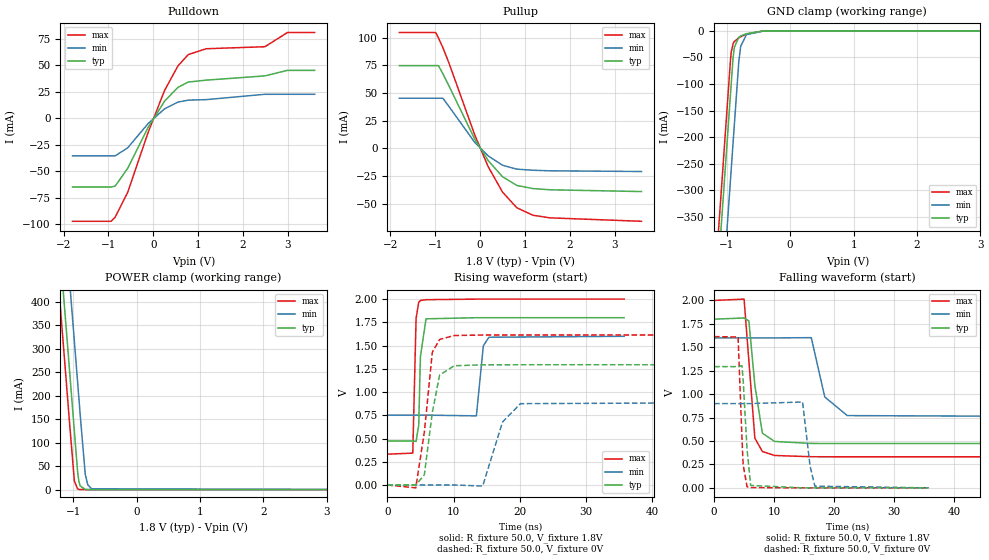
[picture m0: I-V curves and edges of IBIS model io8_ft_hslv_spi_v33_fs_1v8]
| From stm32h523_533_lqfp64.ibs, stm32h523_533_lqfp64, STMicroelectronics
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[Model]   io8_ft_hslv_spi_v33_fs_1v8
Model_type I/O
Polarity   Non-Inverting
Enable   Active-Low
| CAP_THRESHOLD on pad IOFT is "UDTCAPC" :
| Rising=20.0% of vddiom   Falling=80.0% of vddiom
| C_comp min and max val. don't necessarily correlate with the min and max pvt
| but are the smallest and greatest pad capacitance found.
| var   typ   min   max
C_comp   3.69213pF  3.66975pF  3.86731pF
|C_comp_pullup   2.29905pF  2.22610pF  2.22535pF
|C_comp_pulldown   1.39308pF  1.44365pF  1.64196pF
Vinl = 480.0mV
Vinh = 1.4V
Vmeas = 900.0mV   | Reference voltage for timing measurements
Cref  = 50.0pF   | Timing specification test load capacitance value
Rref  = 100.0MOhm   | Timing specification test load resistance value
Vref  = 900.0mV   | Timing specification test load voltage
[Model Spec]
| TIME_THRESHOLD on pin ZIV33M is "CMOS" :
| Rising=40.0% of vddiom   Falling=60.0% of vddiom
Vinl 693.80000mV 621.80000mV 774.80000mV
Vinh 1.05820V 933.20000mV 1.16320V
| variable   typ   min   max
[Temperature Range] 25.0 125.0 -40.0
| variable   typ   min   max
[Voltage Range] 1.8V 1.6V 2.0V
| variable   typ   min   max
[POWER Clamp Reference] 1.8V 1.6V 2.0V
| variable   typ   min   max
[GND Clamp Reference] 0V 0V 0V
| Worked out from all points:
|   slope of the pulldown table from 0 to 0.27 V, typ, clamps not added: 15.8 ohm
|   slope of the pullup table from 0 to 0.27 V, typ, clamps not added: 17.1 ohm
|   GND clamp passes 1 mA (typ) near -0.52 V on its own axis
|   POWER clamp passes 1 mA (typ) near -0.84 V on its own axis
|   rising waveform, R_fixture 50.0, V_fixture 1.8V: 20-80 % time 285ps typ, 440ps min, 245ps max; typ from 0.474 V to 1.8 V
|   falling waveform, R_fixture 50.0, V_fixture 1.8V: 20-80 % time 1.13ns typ, 2.11ns min, 1.05ns max; typ from 1.8 V to 0.474 V
|   rising waveform, R_fixture 50.0, V_fixture 0V: 20-80 % time 1.38ns typ, 2.22ns min, 1.22ns max; typ from 0 V to 1.29 V
|   falling waveform, R_fixture 50.0, V_fixture 0V: 20-80 % time 734ps typ, 1.02ns min, 551ps max; typ from 1.29 V to 0 V
[POWER Clamp]
-1.8V     1.518A     1.709A     1.407A
-1.23V    548.8mA    740.2mA    437.5mA
-1.16V    429.8mA    621.2mA    318.5mA
-1.05V    242.8mA    434.2mA    131.5mA
-980mV    123.8mA    315.2mA    17.95mA
-930mV    38.81mA    230.2mA    1.49mA
-910mV    17.82mA    196.2mA    550.8uA
-890mV    8.18mA     162.2mA    203.5uA
-810mV    363.5uA    33.6mA     3.797uA
-770mV    76.62uA    10.47mA    518.8nA
-710mV    7.416uA    1.822mA    26.33nA
3.6V      0A         0A         0A
[GND Clamp]
-1.8V     -1.579A    -1.74A     -1.515A
-1.24V    -627.3mA   -788.3mA   -562.7mA
-1.05V    -304.3mA   -465.3mA   -239.7mA
-940mV    -117.3mA   -278.3mA   -52.69mA
-930mV    -100.3mA   -261.3mA   -40.52mA
-900mV    -50.11mA   -210.3mA   -24.23mA
-880mV    -30.95mA   -176.3mA   -20.02mA
-810mV    -12.18mA   -57.97mA   -13.23mA
-780mV    -9.807mA   -29.1mA    -11.19mA
-690mV    -5.41mA    -7.142mA   -6.184mA
-420mV    -170.4uA   -446.1uA   -81.94uA
3.6V      5.755nA    953.2nA    228.2pA
| variable   typ   min   max
[Pullup Reference] 1.8V 1.6V 2.0V
| variable   typ   min   max
[Pulldown Reference] 0V 0V 0V
[Pullup]
-1.8V     74.76mA    45.28mA    104.6mA
-990mV    74.76mA    45.28mA    104.6mA
-930mV    74.76mA    45.28mA    99.84mA
-830mV    67.43mA    45.28mA    91.04mA
-680mV    55.26mA    37.06mA    75.52mA
-120mV    8.372mA    5.391mA    12.2mA
180mV     -11.02mA   -6.852mA   -16.51mA
500mV     -25.64mA   -15.26mA   -39.49mA
820mV     -33.51mA   -18.79mA   -53.71mA
1.18V     -36.34mA   -19.79mA   -60.45mA
1.56V     -37.44mA   -20.28mA   -62.79mA
3.6V      -39.03mA   -20.93mA   -65.9mA
[Pulldown]
-1.8V     -65.02mA   -35.56mA   -97.42mA
-940mV    -65.02mA   -35.56mA   -97.42mA
-850mV    -64.17mA   -35.56mA   -93.49mA
-570mV    -47.32mA   -28.01mA   -70.04mA
-120mV    -9.088mA   -5.279mA   -14.07mA
250mV     16.04mA    8.832mA    26.05mA
550mV     29.17mA    15.25mA    49.41mA
780mV     34.17mA    17.07mA    60.14mA
1.18V     35.97mA    17.56mA    65.65mA
2.49V     40mA       22.62mA    67.56mA
2.99V     45.21mA    22.62mA    80.94mA
3.6V      45.21mA    22.62mA    80.94mA
[Ramp]
dV/dt_r 776.15948mV/1.37726ns 539.55921mV/2.1654ns 968.54348mV/1.22042ns
dV/dt_f 795.78715mV/1.12648ns 508.98185mV/1.87644ns 1.00099V/1.03717ns
R_load = 50.0
| Removed startup time: 0s 0s 0s  .
| Removed end time: 35.75ns.
[Rising Waveform]
R_fixture   = 50.0
V_fixture   = 1.8V
V_fixture_min = 1.6V
V_fixture_max = 2.0V
0s        473.7mV    751.7mV    331.7mV
3.85ns    473.7mV    751.7mV    342.8mV
4.35ns    468.7mV    751.7mV    1.792V
4.75ns    642.9mV    751.7mV    1.966V
5ns       1.379V     751.7mV    1.985V
5.85ns    1.788V     751.7mV    1.994V
13.45ns   1.8V       743.8mV    2V
14.5ns    1.8V       1.498V     2V
15.35ns   1.8V       1.59V      2V
35.75ns   1.8V       1.6V       2V
| Removed startup time: 0s 0s 0s  .
| Removed end time: 98.75ns.
[Falling Waveform]
R_fixture   = 50.0
V_fixture   = 1.8V
V_fixture_min = 1.6V
V_fixture_max = 2.0V
0s        1.8V       1.6V       2V
5ns       1.813V     1.6V       2.014V
5.8ns     1.781V     1.6V       1.356V
6.8ns     1.095V     1.6V       529.5mV
8.05ns    583.6mV    1.6V       387.9mV
10.1ns    495.2mV    1.6V       345.5mV
16.2ns    474.1mV    1.603V     332.1mV
18.45ns   473.8mV    969.8mV    331.8mV
22.2ns    473.7mV    771.1mV    331.7mV
98.75ns   473.7mV    751.7mV    331.7mV
| Removed startup time: 0s 0s 0s  .
| Removed end time: 98.6ns.
[Rising Waveform]
R_fixture   = 50.0
V_fixture   = 0V
V_fixture_min = 0V
V_fixture_max = 0V
0s        174.5nV    438.2nV    123.6nV
4.3ns     -1.03mV    437.8nV    -30.91mV
5.6ns     110.8mV    409.4nV    570.7mV
6.8ns     781.2mV    356nV      1.428V
7.9ns     1.183V     290.5nV    1.566V
10.1ns    1.283V     278.9nV    1.608V
14.4ns    1.293V     -11.09mV   1.614V
17.4ns    1.293V     678.1mV    1.614V
20.1ns    1.294V     875.2mV    1.614V
98.6ns    1.294V     899.3mV    1.614V
| Removed startup time: 0s 0s 0s  .
| Removed end time: 35.75ns.
[Falling Waveform]
R_fixture   = 50.0
V_fixture   = 0V
V_fixture_min = 0V
V_fixture_max = 0V
0s        1.294V     899.3mV    1.614V
4ns       1.294V     899.3mV    1.61V
4.65ns    1.303V     899.3mV    532.7mV
4.85ns    1.148V     899.3mV    245.4mV
5.5ns     406.5mV    899.3mV    10.5mV
6.1ns     26.09mV    899.3mV    3.023mV
14.75ns   42.68uV    916.2mV    30.09uV
16ns      26.47uV    232.4mV    16.51uV
16.8ns    20.02uV    18.32mV    11.33uV
35.75ns   156.7nV    11.83uV    32.96nV
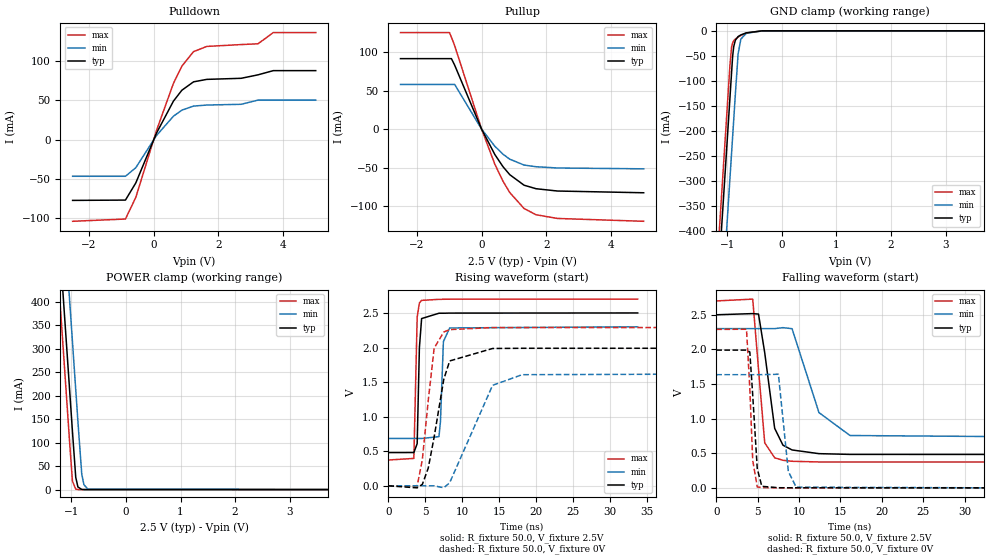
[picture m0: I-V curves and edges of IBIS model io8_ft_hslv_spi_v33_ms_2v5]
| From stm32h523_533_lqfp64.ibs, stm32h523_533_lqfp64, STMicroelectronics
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[Model]   io8_ft_hslv_spi_v33_ms_2v5
Model_type I/O
Polarity   Non-Inverting
Enable   Active-Low
| CAP_THRESHOLD on pad IOFT is "UDTCAPC" :
| Rising=20.0% of vddiom   Falling=80.0% of vddiom
| C_comp min and max val. don't necessarily correlate with the min and max pvt
| but are the smallest and greatest pad capacitance found.
| var   typ   min   max
C_comp   3.86841pF  3.83555pF  3.96274pF
|C_comp_pullup   2.45390pF  2.33575pF  2.34220pF
|C_comp_pulldown   1.41451pF  1.49980pF  1.62054pF
Vinl = 690.0mV
Vinh = 1.89V
Vmeas = 1.25V   | Reference voltage for timing measurements
Cref  = 50.0pF   | Timing specification test load capacitance value
Rref  = 100.0MOhm   | Timing specification test load resistance value
Vref  = 1.25V   | Timing specification test load voltage
[Model Spec]
| TIME_THRESHOLD on pin ZIV33M is "CMOS" :
| Rising=40.0% of vddiom   Falling=60.0% of vddiom
Vinl 978.80000mV 906.80000mV 1.05480V
Vinh 1.39920V 1.29220V 1.48720V
| variable   typ   min   max
[Temperature Range] 25.0 125.0 -40.0
| variable   typ   min   max
[Voltage Range] 2.5V 2.3V 2.7V
| variable   typ   min   max
[POWER Clamp Reference] 2.5V 2.3V 2.7V
| variable   typ   min   max
[GND Clamp Reference] 0V 0V 0V
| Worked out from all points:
|   slope of the pulldown table from 0 to 0.375 V, typ, clamps not added: 11.5 ohm
|   slope of the pullup table from 0 to 0.375 V, typ, clamps not added: 12.3 ohm
|   GND clamp passes 1 mA (typ) near -0.52 V on its own axis
|   POWER clamp passes 1 mA (typ) near -0.84 V on its own axis
|   rising waveform, R_fixture 50.0, V_fixture 2.5V: 20-80 % time 253ps typ, 302ps min, 243ps max; typ from 0.481 V to 2.5 V
|   falling waveform, R_fixture 50.0, V_fixture 2.5V: 20-80 % time 1.32ns typ, 2.74ns min, 855ps max; typ from 2.5 V to 0.481 V
|   rising waveform, R_fixture 50.0, V_fixture 0V: 20-80 % time 1.91ns typ, 3.42ns min, 1.29ns max; typ from 0 V to 1.99 V
|   falling waveform, R_fixture 50.0, V_fixture 0V: 20-80 % time 576ps typ, 771ps min, 459ps max; typ from 1.99 V to 0 V
[POWER Clamp]
-2.5V     2.708A     2.899A     2.597A
-1.23V    548.8mA    740.2mA    437.5mA
-1.16V    429.8mA    621.2mA    318.5mA
-1.12V    361.8mA    553.2mA    250.5mA
-1.03V    208.8mA    400.2mA    97.53mA
-980mV    123.8mA    315.2mA    17.95mA
-920mV    26.3mA     213.2mA    906uA
-880mV    5.543mA    145.2mA    123.7uA
-810mV    363.5uA    33.6mA     3.797uA
-770mV    76.62uA    10.47mA    518.8nA
-700mV    5.026uA    1.361mA    16.09nA
5V        0A         0A         0A
[GND Clamp]
-2.5V     -2.77A     -2.931A    -2.704A
-1.21V    -576.8mA   -738.1mA   -511.3mA
-950mV    -134.8mA   -296.1mA   -69.34mA
-920mV    -83.82mA   -245.1mA   -32.48mA
-900mV    -50.56mA   -211.1mA   -24.02mA
-880mV    -31.31mA   -177.1mA   -19.85mA
-850mV    -18.7mA    -126.1mA   -16.34mA
-800mV    -11.46mA   -46.18mA   -12.45mA
-750mV    -8.203mA   -16.63mA   -9.325mA
-650mV    -4.063mA   -4.987mA   -4.427mA
-360mV    -35.05uA   -165.1uA   -9.564uA
5V        7.96nA     1.282uA    294pA
| variable   typ   min   max
[Pullup Reference] 2.5V 2.3V 2.7V
| variable   typ   min   max
[Pulldown Reference] 0V 0V 0V
[Pullup]
-2.5V     91.39mA    57.92mA    125.2mA
-990mV    91.39mA    57.92mA    125.2mA
-930mV    91.39mA    57.92mA    119.1mA
-830mV    82.91mA    57.92mA    108.2mA
0V        9.32pA     735pA      5.94pA
410mV     -33.05mA   -22.3mA    -45.65mA
660mV     -48.74mA   -32.53mA   -67.55mA
870mV     -59.15mA   -39.06mA   -82.32mA
1.31V     -72.78mA   -46.64mA   -103mA
1.68V     -77.34mA   -48.83mA   -111.1mA
2.34V     -80.33mA   -50.46mA   -115.9mA
5V        -82.59mA   -51.55mA   -119.6mA
[Pulldown]
-2.5V     -77.63mA   -46.85mA   -104.3mA
-870mV    -77.24mA   -46.85mA   -101.4mA
-550mV    -55.3mA    -35.88mA   -73.72mA
90mV      8.401mA    5.299mA    11.79mA
610mV     49.03mA    29.76mA    71.69mA
870mV     62.92mA    37.48mA    93.62mA
1.23V     73.63mA    42.72mA    112.2mA
1.64V     76.78mA    44.01mA    118.8mA
2.7V      78.15mA    44.99mA    121.2mA
3.22V     82.58mA    50.35mA    122.2mA
3.69V     87.93mA    50.35mA    136.5mA
5V        87.93mA    50.35mA    136.5mA
[Ramp]
dV/dt_r 1.19372V/1.90565ns 981.17207mV/3.27343ns 1.37325V/1.28448ns
dV/dt_f 1.21165V/1.3184ns 969.26096mV/2.5059ns 1.39628V/854.52465ps
R_load = 50.0
| Removed startup time: 0s 0s 0s  .
| Removed end time: 33.75ns.
[Rising Waveform]
R_fixture   = 50.0
V_fixture   = 2.5V
V_fixture_min = 2.3V
V_fixture_max = 2.7V
0s        480.6mV    684.6mV    372.9mV
3.45ns    481mV      684.6mV    396.2mV
3.9ns     610.3mV    684.6mV    2.438V
4.2ns     1.997V     684.6mV    2.645V
4.5ns     2.419V     684.6mV    2.682V
6.85ns    2.496V     711.2mV    2.697V
7.05ns    2.496V     930.4mV    2.697V
7.45ns    2.496V     2.087V     2.698V
8.3ns     2.498V     2.283V     2.699V
33.75ns   2.5V       2.3V       2.7V
| Removed startup time: 0s 0s 0s  .
| Removed end time: 98.75ns.
[Falling Waveform]
R_fixture   = 50.0
V_fixture   = 2.5V
V_fixture_min = 2.3V
V_fixture_max = 2.7V
0s        2.5V       2.3V       2.7V
4.4ns     2.517V     2.3V       2.726V
5.1ns     2.51V      2.3V       1.714V
5.85ns    1.952V     2.3V       650mV
7.05ns    860.3mV    2.3V       433.9mV
8.05ns    616.8mV    2.314V     398.6mV
9.15ns    547.5mV    2.299V     383.9mV
12.4ns    494mV      1.087V     374.2mV
16.15ns   483.3mV    756.1mV    373mV
98.75ns   480.6mV    684.6mV    372.9mV
| Removed startup time: 0s 0s 0s  .
| Removed end time: 98.6ns.
[Rising Waveform]
R_fixture   = 50.0
V_fixture   = 0V
V_fixture_min = 0V
V_fixture_max = 0V
0s        177.6nV    421.4nV    141.3nV
3.9ns     -29.8mV    -29.52nV   -3.351mV
4.6ns     21.25mV    -10.44nV   379.2mV
5.4ns     257mV      -1.262uV   1.236V
6.2ns     706.9mV    -10.66uV   1.992V
7.5ns     1.541V     -28.83mV   2.224V
8.3ns     1.806V     44.8mV     2.259V
14.1ns    1.986V     1.453V     2.289V
18.1ns    1.989V     1.607V     2.289V
98.6ns    1.99V      1.635V     2.289V
| Removed startup time: 0s 0s 0s  .
| Removed end time: 33.7ns.
[Falling Waveform]
R_fixture   = 50.0
V_fixture   = 0V
V_fixture_min = 0V
V_fixture_max = 0V
0s        1.99V      1.635V     2.289V
3.65ns    1.99V      1.635V     2.291V
4.05ns    1.962V     1.635V     1.438V
4.4ns     1.339V     1.635V     397.3mV
4.95ns    275.9mV    1.635V     12.97mV
5.5ns     22.3mV     1.635V     3.534mV
7.5ns     1.829mV    1.641V     1.139mV
8.7ns     1.18mV     238.1mV    672.8uV
9.65ns    827.4uV    10.37mV    429.5uV
33.7ns    243.9nV    8.712uV    40.62nV
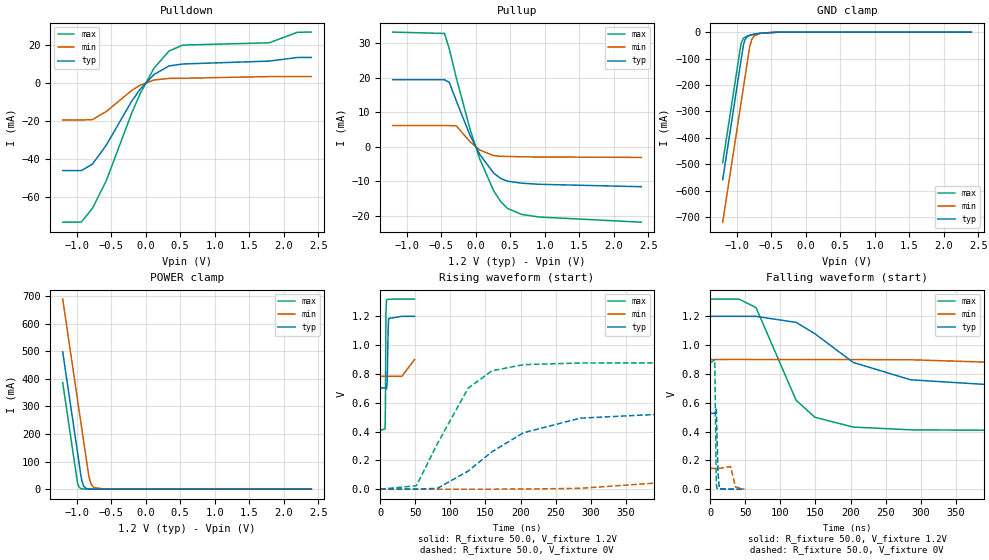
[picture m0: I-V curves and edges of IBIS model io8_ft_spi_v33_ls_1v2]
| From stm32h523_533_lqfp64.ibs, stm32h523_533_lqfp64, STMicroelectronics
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[Model]   io8_ft_spi_v33_ls_1v2
Model_type I/O
Polarity   Non-Inverting
Enable   Active-Low
| CAP_THRESHOLD on pad IOFT is "UDTCAPC" :
| Rising=20.0% of vddiom   Falling=80.0% of vddiom
| C_comp min and max val. don't necessarily correlate with the min and max pvt
| but are the smallest and greatest pad capacitance found.
| var   typ   min   max
C_comp   3.39510pF  3.36975pF  3.42655pF
|C_comp_pullup   2.08510pF  1.99665pF  1.90125pF
|C_comp_pulldown   1.31000pF  1.37310pF  1.52530pF
Vinl = 270.0mV
Vinh = 924.0mV
Vmeas = 600.0mV   | Reference voltage for timing measurements
Cref  = 50.0pF   | Timing specification test load capacitance value
Rref  = 100.0MOhm   | Timing specification test load resistance value
Vref  = 600.0mV   | Timing specification test load voltage
[Model Spec]
| TIME_THRESHOLD on pin ZIV33M is "CMOS" :
| Rising=40.0% of vddiom   Falling=60.0% of vddiom
Vinl 437.80000mV 335.80000mV 479.80000mV
Vinh 728.20000mV 529.20000mV 807.20000mV
| variable   typ   min   max
[Temperature Range] 25.0 125.0 -40.0
| variable   typ   min   max
[Voltage Range] 1.2V 900.0mV 1.32V
| variable   typ   min   max
[POWER Clamp Reference] 1.2V 900.0mV 1.32V
| variable   typ   min   max
[GND Clamp Reference] 0V 0V 0V
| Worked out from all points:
|   slope of the pulldown table from 0 to 0.18 V, typ, clamps not added: 30.6 ohm
|   slope of the pullup table from 0 to 0.18 V, typ, clamps not added: 31.2 ohm
|   GND clamp passes 1 mA (typ) near -0.52 V on its own axis
|   POWER clamp passes 1 mA (typ) near -0.84 V on its own axis
|   rising waveform, R_fixture 50.0, V_fixture 1.2V: 20-80 % time 1.01ns typ, 2.93ns min, 533ps max; typ from 0.704 V to 1.2 V
|   falling waveform, R_fixture 50.0, V_fixture 1.2V: 20-80 % time 102ns typ, 289ns min, 49.7ns max; typ from 1.2 V to 0.704 V
|   rising waveform, R_fixture 50.0, V_fixture 0V: 20-80 % time 102ns typ, 235ns min, 57.7ns max; typ from 0 V to 0.527 V
|   falling waveform, R_fixture 50.0, V_fixture 0V: 20-80 % time 1.79ns typ, 3.92ns min, 1.27ns max; typ from 0.527 V to 0 V
[POWER Clamp]
-1.2V     497.8mA    689.2mA    386.5mA
-990mV    140.8mA    332.2mA    29.53mA
-980mV    123.8mA    315.2mA    17.95mA
-960mV    89.81mA    281.2mA    6.634mA
-930mV    38.81mA    230.2mA    1.49mA
-900mV    12.07mA    179.2mA    334.8uA
-870mV    3.756mA    128.2mA    75.22uA
-820mV    536.4uA    44.98mA    6.246uA
-790mV    166.9uA    18.76mA    1.403uA
-750mV    35.18uA    5.846mA    191.8nA
-590mV    70.09nA    55uA       165.5pA
2.4V      0A         0A         0A
[GND Clamp]
-1.2V     -558.2mA   -719mA     -494.1mA
-940mV    -116.2mA   -277mA     -52.06mA
-930mV    -99.19mA   -260mA     -39.94mA
-900mV    -49.1mA    -209mA     -23.76mA
-880mV    -30.14mA   -175mA     -19.6mA
-850mV    -17.82mA   -124mA     -16.09mA
-810mV    -11.73mA   -56.78mA   -12.91mA
-780mV    -9.444mA   -28.21mA   -10.92mA
-740mV    -7.291mA   -13.16mA   -8.574mA
-640mV    -3.573mA   -4.171mA   -3.954mA
-380mV    -61.75uA   -230.3uA   -20.32uA
2.4V      3.863nA    718.4nA    150.6pA
| variable   typ   min   max
[Pullup Reference] 1.2V 900.0mV 1.32V
| variable   typ   min   max
[Pulldown Reference] 0V 0V 0V
[Pullup]
-1.2V     19.5mA     6.182mA    33.3mA
-450mV    19.5mA     6.182mA    32.91mA
-380mV    18.66mA    6.182mA    28.38mA
-280mV    13.41mA    6.101mA    20.08mA
-80mV     3.305mA    1.497mA    5.124mA
60mV      -2.182mA   -892.7uA   -3.481mA
260mV     -7.556mA   -2.52mA    -12.65mA
360mV     -9.115mA   -2.711mA   -15.76mA
460mV     -9.949mA   -2.774mA   -17.83mA
670mV     -10.53mA   -2.856mA   -19.6mA
920mV     -10.85mA   -2.922mA   -20.34mA
2.4V      -11.55mA   -3.056mA   -21.84mA
[Pulldown]
-1.2V     -46.17mA   -19.61mA   -73.27mA
-930mV    -46.17mA   -19.61mA   -73.18mA
-770mV    -42.8mA    -19.4mA    -66.04mA
-570mV    -32.88mA   -15.17mA   -51.58mA
-200mV    -9.658mA   -4.081mA   -15.89mA
-80mV     -3.488mA   -1.363mA   -5.887mA
120mV     4.232mA    1.386mA    7.501mA
340mV     8.782mA    2.249mA    16.66mA
540mV     9.805mA    2.304mA    19.74mA
1.79V     11.33mA    3.204mA    20.93mA
2.2V      13.23mA    3.204mA    26.48mA
2.4V      13.23mA    3.204mA    26.56mA
[Ramp]
dV/dt_r 315.94084mV/99.05155ns 86.3705mV/233.68849ns 526.34072mV/56.32128ns
dV/dt_f 297.80471mV/100.8476ns 69.85324mV/287.0449ns 547.1392mV/47.66431ns
R_load = 50.0
| Removed startup time: 0s 0s 0s  .
| Removed end time: 48.75ns.
[Rising Waveform]
R_fixture   = 50.0
V_fixture   = 1.2V
V_fixture_min = 900.0mV
V_fixture_max = 1.32V
0s        703.7mV    783.5mV    408.1mV
6.85ns    703.8mV    783.5mV    418.6mV
7.35ns    703.8mV    783.5mV    576.9mV
8.05ns    701.6mV    783.5mV    1.224V
8.95ns    696.9mV    783.5mV    1.313V
9.95ns    758.2mV    783.5mV    1.318V
11.25ns   1.11V      783.5mV    1.319V
11.95ns   1.185V     783.5mV    1.319V
30.7ns    1.2V       783.3mV    1.32V
48.75ns   1.2V       899.7mV    1.32V
| Removed startup time: 0s 0s 0s  .
| Removed end time: 1.99875us.
[Falling Waveform]
R_fixture   = 50.0
V_fixture   = 1.2V
V_fixture_min = 900.0mV
V_fixture_max = 1.32V
0s        1.2V       900mV      1.32V
40.8ns    1.2V       900.9mV    1.32V
65.2ns    1.2V       900mV      1.261V
122.4ns   1.158V     900mV      617.2mV
149.3ns   1.079V     900mV      498.9mV
203.9ns   880mV      899.9mV    431.2mV
285.6ns   759.5mV    898.5mV    412mV
448.7ns   710.3mV    873.8mV    408.2mV
856.6ns   703.7mV    795.2mV    408.1mV
1.999us   703.7mV    783.6mV    408.1mV
| Removed startup time: 0s 0s 0s  .
| Removed end time: 1.9987us.
[Rising Waveform]
R_fixture   = 50.0
V_fixture   = 0V
V_fixture_min = 0V
V_fixture_max = 0V
0s        198.3nV    701.1nV    137nV
51.5ns    -37.12uV   -18.35uV   24.04mV
81.6ns    5.798mV    -14.81uV   316.8mV
125.2ns   125.4mV    10.38uV    700.3mV
159.1ns   259mV      90.47uV    821.4mV
204ns     391.4mV    566uV      864.4mV
285.5ns   493.2mV    6.096mV    876mV
407.9ns   522.5mV    47.45mV    877.1mV
775ns     526.4mV    136.9mV    877.2mV
1.999us   526.6mV    144mV      877.2mV
| Removed startup time: 0s 0s 0s  .
| Removed end time: 48.75ns.
[Falling Waveform]
R_fixture   = 50.0
V_fixture   = 0V
V_fixture_min = 0V
V_fixture_max = 0V
0s        526.6mV    144.1mV    877.3mV
6.4ns     526.4mV    144.1mV    898.8mV
8.35ns    554.8mV    144.1mV    115mV
8.8ns     541.7mV    144.1mV    31.48mV
9.35ns    417.7mV    144.1mV    7.885mV
10.95ns   121.3mV    144.1mV    1.088mV
12.95ns   4.073mV    144.1mV    433uV
28.95ns   78.99uV    157mV      164.9uV
35.85ns   74.85uV    15.7mV     168uV
48.75ns   75.5uV     201.7uV    180.8uV
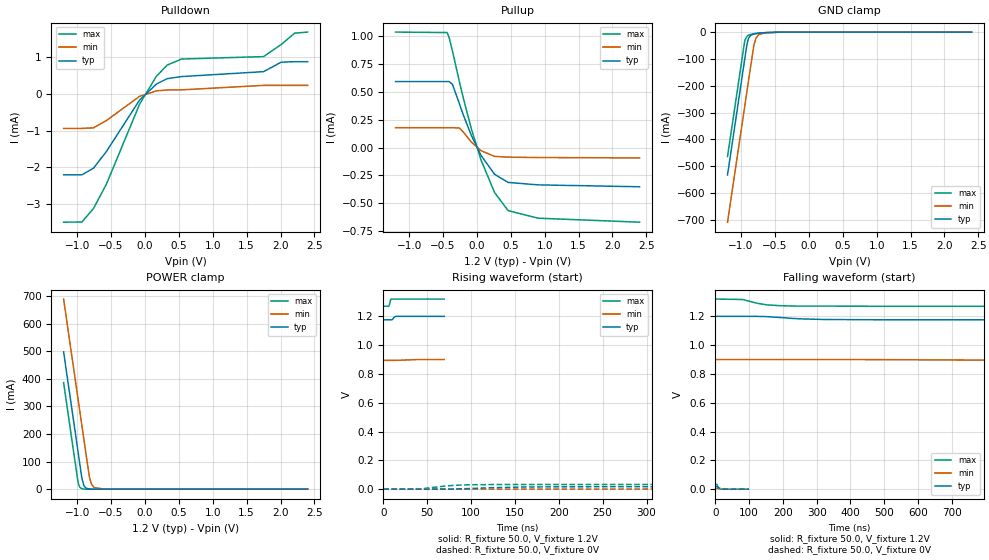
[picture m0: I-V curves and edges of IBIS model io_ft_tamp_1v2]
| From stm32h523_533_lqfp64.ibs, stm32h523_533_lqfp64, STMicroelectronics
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[Model]   io_ft_tamp_1v2
Model_type I/O
Polarity   Non-Inverting
Enable   Active-Low
| CAP_THRESHOLD on pad IOFT is "UDTCAPC" :
| Rising=20.0% of vddios   Falling=80.0% of vddios
| C_comp min and max val. don't necessarily correlate with the min and max pvt
| but are the smallest and greatest pad capacitance found.
| var   typ   min   max
C_comp   2.32855pF  2.30550pF  2.33225pF
|C_comp_pullup   1.28830pF  1.23625pF  1.17640pF
|C_comp_pulldown   1.04025pF  1.06925pF  1.15585pF
Vinl = 270.0mV
Vinh = 924.0mV
Vmeas = 600.0mV   | Reference voltage for timing measurements
Cref  = 50.0pF   | Timing specification test load capacitance value
Rref  = 100.0MOhm   | Timing specification test load resistance value
Vref  = 600.0mV   | Timing specification test load voltage
[Model Spec]
| TIME_THRESHOLD on pin ZIV11 is "CMOS" :
| Rising=40.0% of vdd   Falling=60.0% of vdd
Vinl 447.80000mV 344.80000mV 489.80000mV
Vinh 733.20000mV 535.20000mV 813.20000mV
| variable   typ   min   max
[Temperature Range] 25.0 125.0 -40.0
| variable   typ   min   max
[Voltage Range] 1.2V 900.0mV 1.32V
| variable   typ   min   max
[POWER Clamp Reference] 1.2V 900.0mV 1.32V
| variable   typ   min   max
[GND Clamp Reference] 0V 0V 0V
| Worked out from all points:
|   slope of the pulldown table from 0 to 0.18 V, typ, clamps not added: 636 ohm
|   slope of the pullup table from 0 to 0.18 V, typ, clamps not added: 985 ohm
|   GND clamp passes 1 mA (typ) near -0.57 V on its own axis
|   POWER clamp passes 1 mA (typ) near -0.84 V on its own axis
[POWER Clamp]
-1.2V     497.8mA    689.2mA    386.5mA
-990mV    140.8mA    332.2mA    29.53mA
-980mV    123.8mA    315.2mA    17.95mA
-960mV    89.81mA    281.2mA    6.634mA
-930mV    38.81mA    230.2mA    1.49mA
-900mV    12.07mA    179.2mA    334.8uA
-870mV    3.756mA    128.2mA    75.22uA
-820mV    536.4uA    44.98mA    6.245uA
-790mV    166.9uA    18.76mA    1.403uA
-750mV    35.18uA    5.847mA    191.7nA
-590mV    69.03nA    55.08uA    73.72pA
2.4V      0A         0A         0A
[GND Clamp]
-1.2V     -532.4mA   -708.1mA   -463.6mA
-950mV    -107.4mA   -283.1mA   -38.8mA
-940mV    -90.38mA   -266.1mA   -28.32mA
-910mV    -41.08mA   -215.1mA   -14.73mA
-890mV    -23.27mA   -181.1mA   -11.55mA
-860mV    -12.11mA   -130.1mA   -9.165mA
-810mV    -6.496mA   -47.69mA   -6.855mA
-780mV    -5.135mA   -22.47mA   -5.778mA
-740mV    -3.905mA   -9.483mA   -4.533mA
-650mV    -2.053mA   -2.684mA   -2.298mA
-410mV    -72.31uA   -199.8uA   -32.12uA
2.4V      1.171nA    230.6nA    73.11pA
| variable   typ   min   max
[Pullup Reference] 1.2V 900.0mV 1.32V
| variable   typ   min   max
[Pulldown Reference] 0V 0V 0V
[Pullup]
-1.2V     590uA      177.2uA    1.033mA
-440mV    590uA      177.2uA    1.029mA
-410mV    590uA      177.2uA    984.9uA
-360mV    564.4uA    177.2uA    862.4uA
-260mV    394.5uA    175.5uA    593.3uA
-200mV    290.7uA    137.7uA    441.1uA
-80mV     105.5uA    47.69uA    163.6uA
60mV      -69.43uA   -28.29uA   -110.8uA
260mV     -239uA     -79.03uA   -401.7uA
460mV     -312.2uA   -86.07uA   -564.5uA
900mV     -334uA     -89.44uA   -632.1uA
2.4V      -351uA     -93uA      -668uA
[Pulldown]
-1.2V     -2.205mA   -939uA     -3.496mA
-930mV    -2.205mA   -939uA     -3.491mA
-760mV    -2.025mA   -924uA     -3.125mA
-570mV    -1.573mA   -726.7uA   -2.466mA
-80mV     -167.5uA   -65.77uA   -282.4uA
170mV     271.2uA    84.81uA    486.4uA
330mV     418.2uA    109.1uA    788.5uA
540mV     474.4uA    112.2uA    952.8uA
1.75V     608.4uA    234.1uA    1.019mA
2.01V     867uA      234.1uA    1.349mA
2.21V     879.6uA    234.1uA    1.659mA
2.4V      879.6uA    234.1uA    1.687mA
[Ramp]
dV/dt_r 10.1884mV/50.54075ns 2.6745mV/147.61837ns 19.42497mV/27.59716ns
dV/dt_f 14.6396mV/93.69709ns 3.40962mV/266.03747ns 29.79068mV/54.30082ns
R_load = 50.0
| Removed startup time: 0s 0s 0s  .
| Removed end time: 69.4ns.
[Rising Waveform]
R_fixture   = 50.0
V_fixture   = 1.2V
V_fixture_min = 900.0mV
V_fixture_max = 1.32V
0s        1.176V     894.3mV    1.27V
6.15ns    1.176V     894.3mV    1.27V
6.95ns    1.176V     894.3mV    1.282V
8.2ns     1.176V     894.3mV    1.315V
9.35ns    1.175V     894.3mV    1.32V
10.85ns   1.181V     894.3mV    1.32V
12.3ns    1.194V     894.3mV    1.32V
14.15ns   1.2V       894.3mV    1.32V
38.25ns   1.2V       899.8mV    1.32V
69.4ns    1.2V       900mV      1.32V
| Removed startup time: 0s 0s 0s  .
| Removed end time: 1.9994us.
[Falling Waveform]
R_fixture   = 50.0
V_fixture   = 1.2V
V_fixture_min = 900.0mV
V_fixture_max = 1.32V
0s        1.2V       900mV      1.32V
80.6ns    1.2V       900mV      1.317V
123.5ns   1.2V       900mV      1.291V
151.3ns   1.198V     900mV      1.28V
191.5ns   1.192V     900mV      1.274V
244.9ns   1.183V     900mV      1.271V
326.5ns   1.178V     900mV      1.271V
489.7ns   1.176V     899.4mV    1.27V
897.7ns   1.176V     895mV      1.27V
1.999us   1.176V     894.3mV    1.27V
| Removed startup time: 0s 0s 0s  .
| Removed end time: 1.9994us.
[Rising Waveform]
R_fixture   = 50.0
V_fixture   = 0V
V_fixture_min = 0V
V_fixture_max = 0V
0s        52.19nV    361nV      47.93nV
40.8ns    -18.63uV   -38.57uV   918.6uV
69.9ns    244.5uV    -3.992uV   21.31mV
81.6ns    1.307mV    -3.77uV    26.92mV
96ns      3.966mV    -3.296uV   30.24mV
122.4ns   10.13mV    -201.3nV   31.99mV
163.2ns   15.29mV    26.19uV    32.3mV
244.8ns   16.87mV    343.4uV    32.34mV
571.3ns   16.96mV    4.309mV    32.36mV
1.999us   16.98mV    4.458mV    32.37mV
| Removed startup time: 0s 0s 0s  .
| Removed end time: 99.35ns.
[Falling Waveform]
R_fixture   = 50.0
V_fixture   = 0V
V_fixture_min = 0V
V_fixture_max = 0V
0s        16.99mV    4.472mV    32.38mV
5.15ns    16.97mV    4.473mV    32.93mV
7.7ns     17.32mV    4.471mV    12.99mV
9ns       13.78mV    4.468mV    6.045mV
10.15ns   10.74mV    4.466mV    2.613mV
13.35ns   4.361mV    4.471mV    496.8uV
16.25ns   1.411mV    4.47mV     140.5uV
23.4ns    117.5uV    3.421mV    33.72uV
42.6ns    11.15uV    426.8uV    9.046uV
99.35ns   5.24uV     5.196uV    12.91uV
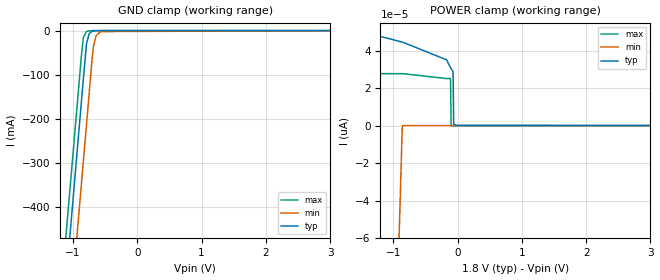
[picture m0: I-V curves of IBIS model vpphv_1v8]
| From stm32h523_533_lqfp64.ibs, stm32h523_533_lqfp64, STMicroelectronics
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[Model]   vpphv_1v8
Model_type Input
Polarity   Non-Inverting
Enable   Active-Low
| CAP_THRESHOLD on pad VPPHV is "UDTCAPC" :
| Rising=20.0% of vddiom   Falling=80.0% of vddiom
| C_comp min and max val. don't necessarily correlate with the min and max pvt
| but are the smallest and greatest pad capacitance found.
| var   typ   min   max
C_comp   1.81506pF  1.80614pF  1.95827pF
|C_comp_pullup   595.80500fF  585.07500fF  589.82000fF
|C_comp_pulldown   1.21925pF  1.22106pF  1.36845pF
Vinl = 480.0mV
Vinh = 1.4V
[Model Spec]
| TIME_THRESHOLD on pin ZIV11 is "CMOS" :
| Rising=40.0% of vdd   Falling=60.0% of vdd
Vinl 544.80000mV 486.80000mV 597.80000mV
Vinh 813.20000mV 730.20000mV 856.20000mV
| variable   typ   min   max
[Temperature Range] 25.0 125.0 -40.0
| variable   typ   min   max
[Voltage Range] 1.8V 1.6V 2.0V
| variable   typ   min   max
[POWER Clamp Reference] 1.8V 1.6V 2.0V
| variable   typ   min   max
[GND Clamp Reference] 0V 0V 0V
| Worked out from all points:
|   GND clamp passes 1 mA (typ) near -0.68 V on its own axis
[POWER Clamp]
-1.8V     52.62pA    -1.131nA   27.7pA
-1.05V    46.23pA    -227.6pA   27.7pA
-1.04V    46.14pA    -215.7pA   27.7pA
-860mV    44.51pA    -700fA     27.7pA
-850mV    44.43pA    0A         27.7pA
-170mV    35.06pA    0A         25.1pA
-110mV    30.96pA    0A         25.1pA
-100mV    30.32pA    0A         0A
-70mV     28.9pA     0A         0A
-60mV     890fA      0A         0A
-30mV     140fA      0A         0A
3.6V      0A         0A         0A
[GND Clamp]
-1.8V     -1.743A    -1.929A    -1.639A
-1.24V    -791.1mA   -977.2mA   -686.6mA
-1.05V    -468.1mA   -654.2mA   -363.6mA
-870mV    -162.1mA   -348.2mA   -57.62mA
-840mV    -111.1mA   -297.2mA   -16.04mA
-790mV    -29.68mA   -212.2mA   -2.176mA
-750mV    -7.178mA   -144.2mA   -636.5uA
-700mV    -1.551mA   -59.19mA   -154uA
-680mV    -901.1uA   -33.78mA   -95.77uA
-640mV    -306.8uA   -11.44mA   -47.96uA
-570mV    -42.87uA   -2.136mA   -18.51uA
3.6V      1.009nA    8.282nA    2.115nA
